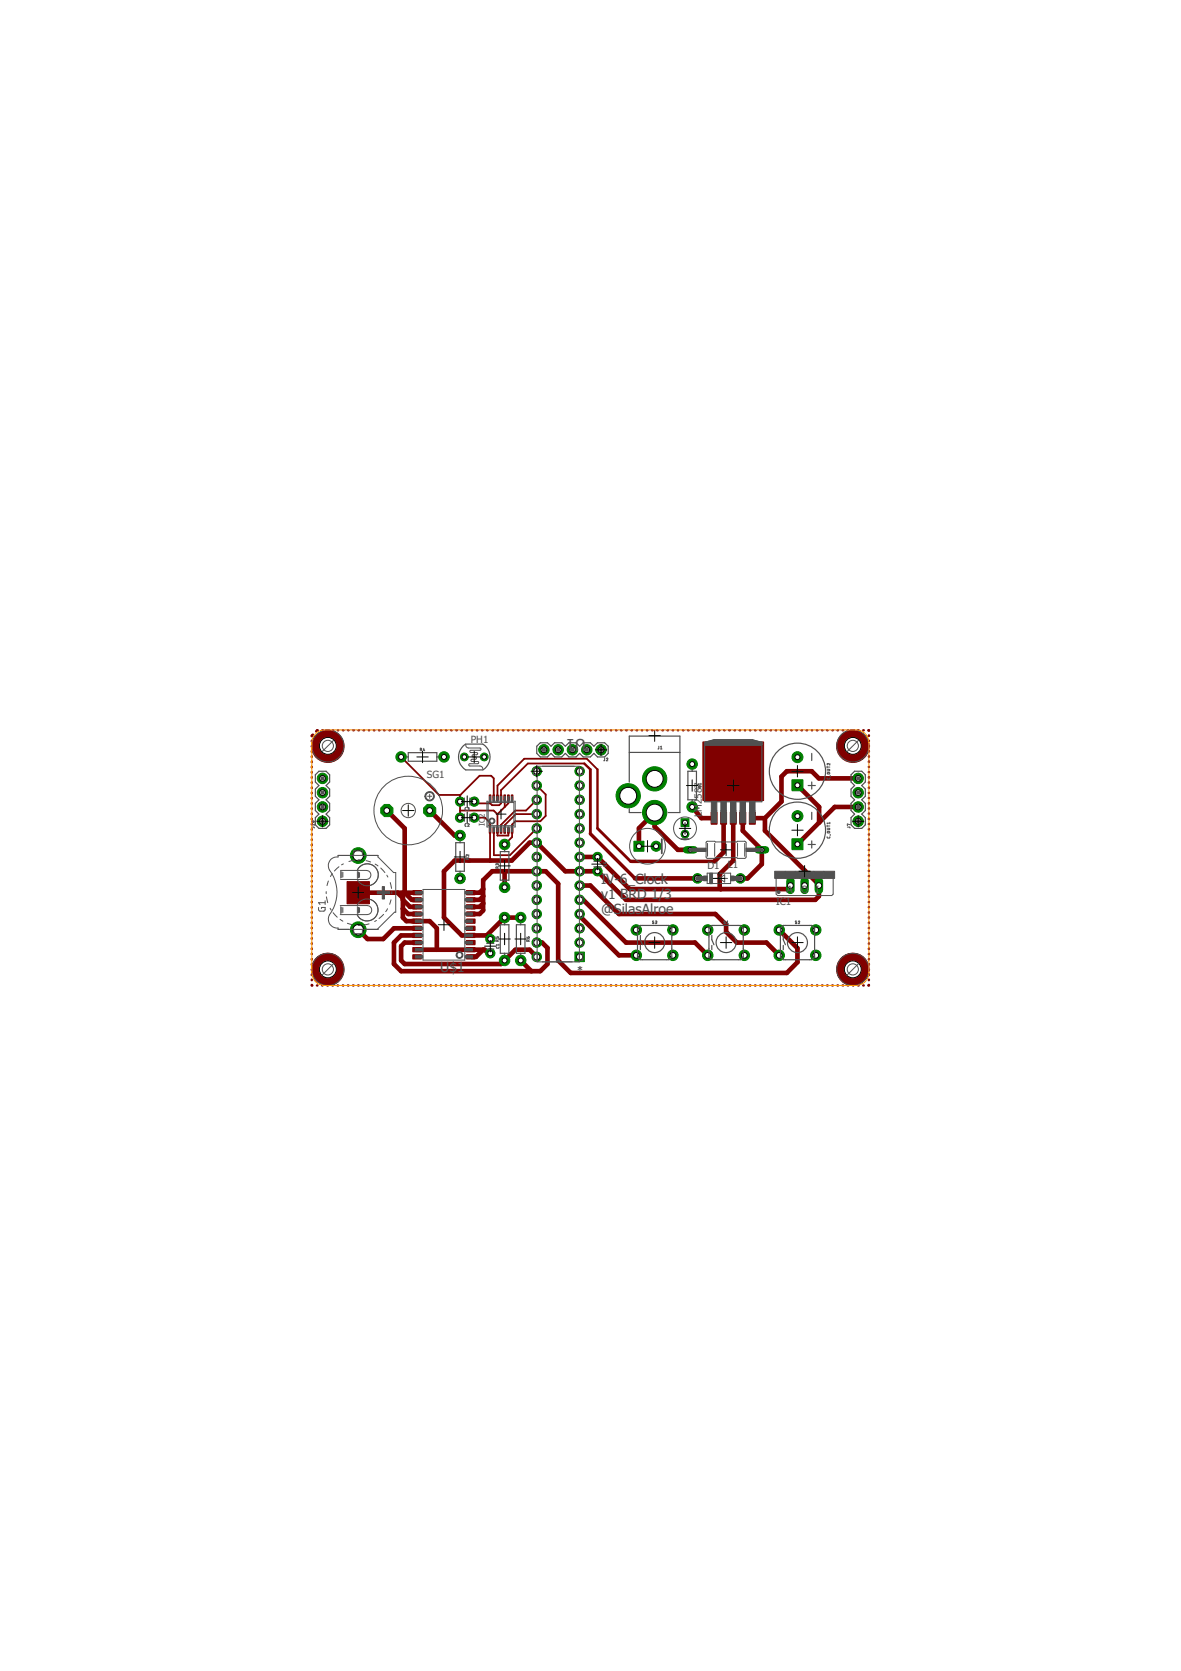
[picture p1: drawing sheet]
<svg xmlns="http://www.w3.org/2000/svg" width="210mm" height="297mm" viewBox="0 0 210 297" stroke-linecap="round" stroke-linejoin="round" font-family="sans-serif">
<defs><g id="words">
<text font-size="2.9" fill="#505050" x="104.1" y="131.3" transform="rotate(-180 104.1 131.3)">U1</text>
<g font-size="2.5" fill="#505050">
<text x="106.8" y="157.2">IV-6_Clock</text>
<text x="106.8" y="159.8">v1 BRD 1/3</text>
<text x="106.8" y="162.5">@SilasAlroe</text>
<text x="78.2" y="172.8">U$1</text>
</g>
<g font-size="1.8" fill="#505050">
<text x="83.7" y="132">PH1</text>
<text x="75.9" y="138.4">SG1</text>
<text x="124.7" y="145.2" transform="rotate(-90 124.7 145.2)">LM2587</text>
<text x="125.7" y="154.5">D1</text>
<text x="129.3" y="154.2">L1</text>
<text x="137.9" y="160.9">IC1</text>
<text x="139.8" y="158.7">A</text>
<text x="142.4" y="158.7">O</text>
<text x="144.9" y="158.7">I</text>
<text x="103.6" y="171.2" transform="rotate(-180 103.6 171.2)">*</text>
</g>
<text font-size="1.4" fill="#505050" x="86.2" y="146.8" transform="rotate(-90 86.2 146.8)">IC2</text>
</g></defs>
<g fill="#800000" stroke="#800000" stroke-width=".18">
<path d="M124.9 131.9h10.8v10.4h-10.8z"/>
<path d="M126.4 144.4h1v2.1h-1z"/>
<path d="M128.1 144.4h1v2.1h-1z"/>
<path d="M129.8 144.4h1.1v2.1h-1.1z"/>
<path d="M131.5 144.4h1v2.1h-1z"/>
<path d="M133.2 144.4h1v2.1h-1z"/>
<path d="M82.9 169.7h1.5v.8h-1.5z"/>
<path d="M82.9 168.4h1.5v.8h-1.5z"/>
<path d="M82.9 167.2h1.5v.7h-1.5z"/>
<path d="M82.9 165.9h1.5v.8h-1.5z"/>
<path d="M82.9 164.6h1.5v.8h-1.5z"/>
<path d="M82.9 163.4h1.5v.7h-1.5z"/>
<path d="M82.9 162.1h1.5v.8h-1.5z"/>
<path d="M82.9 160.8h1.5v.8h-1.5z"/>
<path d="M82.9 159.6h1.5v.7h-1.5z"/>
<path d="M82.9 158.3h1.5v.8h-1.5z"/>
<path d="M73.4 159.6h1.5v.7h-1.5z"/>
<path d="M73.4 158.3h1.5v.8h-1.5z"/>
<path d="M73.4 160.8h1.5v.8h-1.5z"/>
<path d="M73.4 162.1h1.5v.8h-1.5z"/>
<path d="M73.4 163.4h1.5v.7h-1.5z"/>
<path d="M73.4 164.6h1.5v.8h-1.5z"/>
<path d="M73.4 165.9h1.5v.8h-1.5z"/>
<path d="M73.4 167.2h1.5v.7h-1.5z"/>
<path d="M73.4 168.4h1.5v.8h-1.5z"/>
<path d="M73.4 169.7h1.5v.8h-1.5z"/>
<path d="M61.7 156.7h4v4h-4z"/>
<path d="M87 147.2h.2v.9h-.2z"/>
<path d="M87.6 147.2h.3v.9h-.3z"/>
<path d="M88.3 147.2h.3v.9h-.3z"/>
<path d="M88.9 147.2h.3v.9h-.3z"/>
<path d="M89.6 147.2h.3v.9h-.3z"/>
<path d="M90.2 147.2h.3v.9h-.3z"/>
<path d="M90.9 147.2h.3v.9h-.3z"/>
<path d="M90.9 141.3h.3v1h-.3z"/>
<path d="M90.2 141.3h.3v1h-.3z"/>
<path d="M89.6 141.3h.3v1h-.3z"/>
<path d="M88.9 141.3h.3v1h-.3z"/>
<path d="M88.3 141.3h.3v1h-.3z"/>
<path d="M87.6 141.3h.3v1h-.3z"/>
<path d="M87 141.3h.2v1h-.2z"/>
</g>
<g fill="none" stroke="#800000" stroke-width=".42">
<path d="M55.4 131.7v.1M55.4 132.6v.1M55.4 133.5v.1M55.4 134.5v.1M55.4 135.4v.1M55.4 136.3v.1M55.4 137.2v.1M55.4 138.1v.2M55.4 139.1v.1M55.4 140v.1M55.6 130.6l-.2 .3M56.5 129.8l-.3 .2"/>
<path d="M57.3 129.8h.1M58.2 129.8h.1M59.1 129.8h.1M60 129.8h.1M60.9 129.8h.1M61.9 129.8h.1M62.8 129.8h.1M63.7 129.8h.1M64.6 129.8h.1M65.5 129.8h.1M66.4 129.8h.1M67.4 129.8h.1"/>
<path d="M68.3 129.8h.1M69.2 129.8h.1M70.1 129.8h.1M71 129.8h.1M71.9 129.8h.1M72.9 129.8h.1M73.8 129.8h.1M74.7 129.8h.1M75.6 129.8h.1M76.5 129.8h.1M77.4 129.8h.1M78.3 129.8h.1"/>
<path d="M79.2 129.8h.2M80.2 129.8h.1M81.1 129.8h.1M82 129.8h.1M82.9 129.8h.1M83.8 129.8h.1M84.8 129.8h.1M85.7 129.8h.1M86.6 129.8h.1M87.5 129.8h.1M88.4 129.8h.1M89.3 129.8h.1"/>
<path d="M90.2 129.8h.1M91.2 129.8h.1M92.1 129.8h.1M93 129.8h.1M93.9 129.8h.1M94.8 129.8h.1M95.7 129.8h.1M96.6 129.8h.2M97.6 129.8h.1M98.5 129.8h.1M99.4 129.8h.1M100.3 129.8h.1"/>
<path d="M101.2 129.8h.1M102.2 129.8h.1M103.1 129.8h.1M103.8 135.7l1.1 1.1M104 129.8h.1M104.9 129.8h.1M105.8 129.8h.1M106.2 136.8v10.5M106.7 129.8h.1M107.6 129.8h.1M108.6 129.8h.1M109.5 129.8h.1"/>
<path d="M110.4 129.8h.1M111.3 129.8h.1M112.2 129.8h.1M113.1 129.8h.1M114 129.8h.2M115 129.8h.1M115.9 129.8h.1M116.8 129.8h.1M117.7 129.8h.1M118.6 129.8h.1M119.5 129.8h.2M120.5 129.8h.1"/>
<path d="M121.4 129.8h.1M122.3 129.8h.1M123.2 129.8h.1M124.1 129.8h.1M125 129.8h.1M125.9 129.8h.1M126.9 129.8h.1M127.8 129.8h.1M128.7 129.8h.1M129.6 129.8h.1M130.5 129.8h.1M131.4 129.8h.2"/>
<path d="M132.4 129.8h.1M133.3 129.8h.1M134.2 129.8h.1M135.1 129.8h.1M136 129.8h.1M136.9 129.8h.1M137.9 129.8h.1M138.8 129.8h.1M139.7 129.8h.1M140.6 129.8h.1M141.5 129.8h.1M142.4 129.8h.1"/>
<path d="M143.3 129.8h.1M144.3 129.8h.1M145.2 129.8h.1M146.1 129.8h.1M147 129.8h.1M147.9 129.8h.1M148.8 129.8h.1M149.8 129.8h.1M150.7 129.8h.1M151.6 129.8h.1M152.5 129.8h.1M153.4 129.8h.1"/>
<path d="M154.3 129.8l.1 .1M154.4 130.7v.1M154.4 131.7v.1M154.4 132.6v.1M154.4 133.5v.1M154.4 134.4v.1M154.4 135.3v.2M154.4 136.3v.1M154.4 137.2v.1M154.4 138.1v.1M154.4 139v.1M154.4 140v.1"/>
<path d="M55.4 140.9v.1M55.4 141.8v.1M55.4 142.7v.2M55.4 143.7v.1M55.4 144.6v.1M55.4 145.5v.1M55.4 146.5v.1M55.4 147.4v.1M55.4 148.3v.1M55.4 149.2v.1M55.4 150.1v.2M55.4 151.1v.1"/>
<path d="M55.4 152v.1M55.4 152.9v.1M55.4 153.8v.1M55.4 154.7v.2M55.4 155.7v.1M55.4 156.6v.1M55.4 157.5v.1M55.4 158.5v.1M55.4 159.4v.1M154.4 140.9v.1M154.4 141.8v.1M154.4 142.7v.2"/>
<path d="M154.4 143.7v.1M154.4 144.6v.1M154.4 145.5v.1M154.4 146.4v.1M154.4 147.4v.1M154.4 148.3v.1M154.4 149.2v.1M154.4 150.1v.1M154.4 151v.2M154.4 152v.1M154.4 152.9v.1M154.4 153.8v.1"/>
<path d="M154.4 154.7v.2M154.4 155.7v.1M154.4 156.6v.1M154.4 157.5v.1M154.4 158.4v.2M154.4 159.4v.1M55.4 160.3v.1M55.4 161.2v.1M55.4 162.1v.1M55.4 163.1v.1M55.4 164v.1M55.4 164.9v.1"/>
<path d="M55.4 165.8v.1M55.4 166.8v.1M55.4 167.7v.1M55.4 168.6v.1M55.4 169.5v.1M55.4 170.5v.1M55.4 171.4v.1M55.4 172.3v.1M55.4 173.2v.1M55.4 174.1v.1M55.4 175.1l.1 .1M56.3 175.2h.1"/>
<path d="M57.3 175.2h.1M58.2 175.2h.1M59.1 175.2h.1M60 175.2h.1M60.9 175.2h.1M61.8 175.2h.1M62.7 175.2h.1M63.6 175.2h.2M64.6 175.2h.1M65.5 175.2h.1M66.4 175.2h.1M67.3 175.2h.1"/>
<path d="M68.2 175.2h.1M69.2 175.2h.1M70.1 175.2h.1M71 175.2h.1M71.9 175.2h.1M72.8 175.2h.1M73.7 175.2h.1M74.7 175.2h.1M75.6 175.2h.1M76.5 175.2h.1M77.4 175.2h.1M78.3 175.2h.1"/>
<path d="M79.2 175.2h.1M80.1 175.2h.1M81.1 175.2h.1M82 175.2h.1M82.9 175.2h.1M83.8 175.2h.1M84.7 175.2h.1M85.6 175.2h.1M86.6 175.2h.1M87.5 175.2h.1M88.4 175.2h.1M89.3 175.2h.1"/>
<path d="M90.2 175.2h.1M91.1 175.2h.1M92.1 175.2h.1M93 175.2h.1M93.9 175.2h.1M94.8 175.2h.1M95.7 175.2h.1M96.6 175.2h.1M97.6 175.2h.1M98.5 175.2h.1M99.4 175.2h.1M100.3 175.2h.1"/>
<path d="M101.2 175.2h.1M102.1 175.2h.1M103 175.2h.1M103.9 175.2h.2M104.9 175.2h.1M105.8 175.2h.1M106.7 175.2h.1M107.6 175.2h.1M108.5 175.2h.1M109.5 175.2h.1M110.4 175.2h.1M111.3 175.2h.1"/>
<path d="M112.2 175.2h.1M113.1 175.2h.1M114 175.2h.1M115 175.2h.1M115.9 175.2h.1M116.8 175.2h.1M117.7 175.2h.1M118.6 175.2h.1M119.5 175.2h.1M120.4 175.2h.1M121.4 175.2h.1M122.3 175.2h.1"/>
<path d="M123.2 175.2h.1M124.1 175.2h.1M125 175.2h.1M125.9 175.2h.1M126.9 175.2h.1M127.8 175.2h.1M128.7 175.2h.1M129.6 175.2h.1M130.5 175.2h.1M131.4 175.2h.1M132.4 175.2h.1M133.3 175.2h.1"/>
<path d="M134.2 175.2h.1M135.1 175.2h.1M136 175.2h.1M136.9 175.2h.1M137.8 175.2h.1M138.8 175.2h.1M139.7 175.2h.1M140.6 175.2h.1M141.5 175.2h.1M142.4 175.2h.1M143.3 175.2h.1M144.3 175.2h.1"/>
<path d="M145.2 175.2h.1M146.1 175.2h.1M147 175.2h.1M147.9 175.2h.1M148.8 175.2h.1M149.8 175.2h.1M150.7 175.2h.1M151.6 175.2h.1M152.5 175.2h.1M153.4 175.2h.1M154.4 160.3v.1M154.4 161.2v.1"/>
<path d="M154.4 162.1v.1M154.4 163v.2M154.4 164v.1M154.4 164.9v.1M154.4 165.8v.1M154.4 166.8v.1M154.4 167.7v.1M154.4 168.6v.1M154.4 169.5v.1M154.4 170.5v.1M154.4 171.4v.1M154.4 172.3v.1"/>
<path d="M154.4 173.2v.1M154.4 174.1v.1M154.4 175.1l-.1 .1"/>
</g>
<g fill="none" stroke="#800000" stroke-width=".83">
<path d="M141.7 139.6l3.9 3.8v2.8M152.5 138.4h-7l-1.2-1.3h-4.5l-.9 .9v4.5l-2.9 2.9M63.7 158.7h10.4M68.7 144.1l3.2 3.2v11.4l1.3 1.3h.9M70.7 158.7l.9 .9M71.6 158.7v4.4l.6 .6h4.2l1.2 1.3v3.8M71.6 160l1.3 1.2h1.2M76.4 144.1l4.4 4.4h1M85.9 158.1l-.7 .6h-1.5M85.9 159.3l-.7 .7h-1.5M89.7 154.9v2.8M103 157.4h1.9l5.1 5.1h17.1l2 1.9v1.3l1.9 1.9h5.2l2.3 2.2"/>
<path d="M103 160h.7l7.6 7.6h12.2l2.3 2.2M103 152.3h3.2l5.7 5.8h27.9l.7-.7M112.9 156.1h11.1M116.4 144.4h.5M116.4 144.4l-2.8 2.8v3.2M116.4 144.4v2.5l4.1 4.2h2.2M123 143.4l1.7 2h2.2M128.6 145.4v6.1l-1.6 1.6M130.3 145.4v7.6l-2.4 2.4v2.5l.2 .2M132 145.4v2.3l3.4 3.4v2.5l-2.5 2.5h-1.3M133.7 145.4h2.3M136 145.4v2.3l9.5 9.5v2.1l-.6 .7h-33.6l-5.1-5.1h-5.7l-5.1-5.1h-1.3l-3.1 3.2h-10.2l-1.9 1.9v8.2l3.2 3.2h4.4"/>
<path d="M152.5 143.4h-4.1l-6.7 6.7v-.6M71.6 161.5l1 1h1.5M74.1 168.8h12l.7 .7h.3M74.1 167.6h-2.2l-.6 .6v2.5l.6 .7h17.1l2.6-2.6h2.5l1.3 1.3M74.1 166.3h-2.8l-1.3 1.3v3.8l1.3 1.2h24.7l1.3-1.2v-2.9l-.9-.9h-1M74.1 165h-4.1l-1.9 1.9h-2.8l-1.6-1.6M83.7 162.5h1.5l.7-.7v-5.3l1.6-1.6h9.5l2.2 2.2v13.6l2.2 2.3h38.4l1.9-2v-2.4l-3.2-3.3M85.9 160.6l-.7 .6h-1.5M85.9 168.8l-1.3 1.3h-.9M86.5 166.3l.6 .6M92.5 163.1h-2.8l-3.2 3.2M92.5 170.7l1.9 1.9"/>
<path d="M103 162.5h-.3l7.3 7.3h3.1"/>
</g>
<g fill="none" stroke="#800000" stroke-width=".32">
<path d="M71.3 134.6l6.7 6.7h3.8M95.4 139.6l1.6 1.6v3.8l-1 1h-4.4l-.6 .6v2.2l-1.3 1.3M103.8 135.7h-10l-4.8 4.8v2.3l-.3 .3h-1.2l-.4-.3v-1M106.2 136.8l-1.9-1.9h-11.1l-4.8 4.8v2.1M81.8 144.1h5.9l.7 .6M81.8 141.3l3.4-3.4h2.1l.5 .5v3.4M81.8 141.3v4.1M83.3 152.9l.1 .1M84.3 145.4h1.9l.9 .9v6.7M84.3 142.5l.3 .3h2.5M88.4 144.7v3.8h1.9l.1-.9M89.7 141.8v1.6"/>
<path d="M90.4 141.8v1l-2 1.9M95.4 144.7h-3.7l-2 2v.9M95.4 142.2l-1.9 1.9h-1.9l-2.6 2.5v1M95.4 147.3l-4.8 4.7h-2.8v-4.4"/>
</g>
<path d="M104.9 136.8v11.4M106.2 147.3l5.9 5.8h.1" fill="none" stroke="#800000" stroke-width=".51"/>
<path d="M104.9 148.2l8 7.9M112.2 153.1h14.8" fill="none" stroke="#800000" stroke-width=".61"/>
<circle cx="121.8" cy="148.3" r=".7" fill="#008000" stroke="#008000" stroke-width=".18"/>
<circle cx="121.8" cy="148.3" r=".44" fill="#fff" stroke="#000" stroke-width=".18"/>
<path d="M121.1 145.5h1.3v1.4h-1.3z" fill="#008000" stroke="#008000" stroke-width=".18"/>
<circle cx="121.8" cy="146.2" r=".44" fill="#fff" stroke="#000" stroke-width=".18"/>
<path d="M112.7 149.5h1.7v1.8h-1.7z" fill="#008000" stroke="#008000" stroke-width=".18"/>
<circle cx="113.6" cy="150.4" r=".44" fill="#fff" stroke="#000" stroke-width=".18"/>
<circle cx="116.6" cy="150.4" r=".89" fill="#008000" stroke="#008000" stroke-width=".18"/>
<circle cx="116.6" cy="150.4" r=".44" fill="#fff" stroke="#000" stroke-width=".18"/>
<circle cx="141.7" cy="145.1" r=".97" fill="#008000" stroke="#008000" stroke-width=".18"/>
<circle cx="141.7" cy="145.1" r=".44" fill="#fff" stroke="#000" stroke-width=".18"/>
<path d="M140.8 149.1h1.9v1.9h-1.9z" fill="#008000" stroke="#008000" stroke-width=".18"/>
<circle cx="141.7" cy="150.1" r=".44" fill="#fff" stroke="#000" stroke-width=".18"/>
<circle cx="141.7" cy="134.6" r=".97" fill="#008000" stroke="#008000" stroke-width=".18"/>
<circle cx="141.7" cy="134.6" r=".44" fill="#fff" stroke="#000" stroke-width=".18"/>
<path d="M140.8 138.6h1.9v2h-1.9z" fill="#008000" stroke="#008000" stroke-width=".18"/>
<circle cx="141.7" cy="139.6" r=".44" fill="#fff" stroke="#000" stroke-width=".18"/>
<circle cx="124" cy="156.1" r=".85" fill="#008000" stroke="#008000" stroke-width=".18"/>
<circle cx="124" cy="156.1" r=".55" fill="#fff" stroke="#000" stroke-width=".18"/>
<circle cx="131.6" cy="156.1" r=".85" fill="#008000" stroke="#008000" stroke-width=".18"/>
<circle cx="131.6" cy="156.1" r=".55" fill="#fff" stroke="#000" stroke-width=".18"/>
<path d="M134.7 151.1h1.4" fill="none" stroke="#008000" stroke-width="1.3"/>
<circle cx="135.4" cy="151.1" r=".4" fill="#fff" stroke="#000" stroke-width=".18"/>
<path d="M122 151.1h1.4" fill="none" stroke="#008000" stroke-width="1.3"/>
<circle cx="122.7" cy="151.1" r=".4" fill="#fff" stroke="#000" stroke-width=".18"/>
<circle cx="123" cy="135.8" r=".93" fill="#008000" stroke="#008000" stroke-width=".18"/>
<circle cx="123" cy="135.8" r=".44" fill="#fff" stroke="#000" stroke-width=".18"/>
<circle cx="123" cy="143.4" r=".93" fill="#008000" stroke="#008000" stroke-width=".18"/>
<circle cx="123" cy="143.4" r=".44" fill="#fff" stroke="#000" stroke-width=".18"/>
<circle cx="116.4" cy="144.4" r="2.16" fill="#008000" stroke="#008000" stroke-width=".18"/>
<circle cx="116.4" cy="144.4" r="1.5" fill="#fff" stroke="#000" stroke-width=".18"/>
<circle cx="116.4" cy="138.5" r="2.16" fill="#008000" stroke="#008000" stroke-width=".18"/>
<circle cx="116.4" cy="138.5" r="1.5" fill="#fff" stroke="#000" stroke-width=".18"/>
<circle cx="111.7" cy="141.5" r="2.16" fill="#008000" stroke="#008000" stroke-width=".18"/>
<circle cx="111.7" cy="141.5" r="1.5" fill="#fff" stroke="#000" stroke-width=".18"/>
<circle cx="152.5" cy="146" r=".93" fill="#008000" stroke="#008000" stroke-width=".18"/>
<circle cx="152.5" cy="146" r=".51" fill="#fff" stroke="#000" stroke-width=".18"/>
<circle cx="152.5" cy="143.4" r=".93" fill="#008000" stroke="#008000" stroke-width=".18"/>
<circle cx="152.5" cy="143.4" r=".51" fill="#fff" stroke="#000" stroke-width=".18"/>
<circle cx="152.5" cy="140.9" r=".93" fill="#008000" stroke="#008000" stroke-width=".18"/>
<circle cx="152.5" cy="140.9" r=".51" fill="#fff" stroke="#000" stroke-width=".18"/>
<circle cx="152.5" cy="138.4" r=".93" fill="#008000" stroke="#008000" stroke-width=".18"/>
<circle cx="152.5" cy="138.4" r=".51" fill="#fff" stroke="#000" stroke-width=".18"/>
<circle cx="57.3" cy="146" r=".93" fill="#008000" stroke="#008000" stroke-width=".18"/>
<circle cx="57.3" cy="146" r=".51" fill="#fff" stroke="#000" stroke-width=".18"/>
<circle cx="57.3" cy="143.4" r=".93" fill="#008000" stroke="#008000" stroke-width=".18"/>
<circle cx="57.3" cy="143.4" r=".51" fill="#fff" stroke="#000" stroke-width=".18"/>
<circle cx="57.3" cy="140.9" r=".93" fill="#008000" stroke="#008000" stroke-width=".18"/>
<circle cx="57.3" cy="140.9" r=".51" fill="#fff" stroke="#000" stroke-width=".18"/>
<circle cx="57.3" cy="138.4" r=".93" fill="#008000" stroke="#008000" stroke-width=".18"/>
<circle cx="57.3" cy="138.4" r=".51" fill="#fff" stroke="#000" stroke-width=".18"/>
<circle cx="86.1" cy="134.6" r=".7" fill="#008000" stroke="#008000" stroke-width=".18"/>
<circle cx="86.1" cy="134.6" r=".4" fill="#fff" stroke="#000" stroke-width=".18"/>
<circle cx="82.5" cy="134.6" r=".7" fill="#008000" stroke="#008000" stroke-width=".18"/>
<circle cx="82.5" cy="134.6" r=".4" fill="#fff" stroke="#000" stroke-width=".18"/>
<circle cx="71.3" cy="134.6" r=".93" fill="#008000" stroke="#008000" stroke-width=".18"/>
<circle cx="71.3" cy="134.6" r=".44" fill="#fff" stroke="#000" stroke-width=".18"/>
<circle cx="78.9" cy="134.6" r=".93" fill="#008000" stroke="#008000" stroke-width=".18"/>
<circle cx="78.9" cy="134.6" r=".44" fill="#fff" stroke="#000" stroke-width=".18"/>
<circle cx="125.8" cy="165.3" r=".93" fill="#008000" stroke="#008000" stroke-width=".18"/>
<circle cx="125.8" cy="165.3" r=".51" fill="#fff" stroke="#000" stroke-width=".18"/>
<circle cx="132.3" cy="165.3" r=".93" fill="#008000" stroke="#008000" stroke-width=".18"/>
<circle cx="132.3" cy="165.3" r=".51" fill="#fff" stroke="#000" stroke-width=".18"/>
<circle cx="125.8" cy="169.8" r=".93" fill="#008000" stroke="#008000" stroke-width=".18"/>
<circle cx="125.8" cy="169.8" r=".51" fill="#fff" stroke="#000" stroke-width=".18"/>
<circle cx="132.3" cy="169.8" r=".93" fill="#008000" stroke="#008000" stroke-width=".18"/>
<circle cx="132.3" cy="169.8" r=".51" fill="#fff" stroke="#000" stroke-width=".18"/>
<path d="M140.5 156.7v1.5" fill="none" stroke="#008000" stroke-width="1.5"/>
<circle cx="140.5" cy="157.4" r=".51" fill="#fff" stroke="#000" stroke-width=".18"/>
<path d="M143 156.7v1.5" fill="none" stroke="#008000" stroke-width="1.5"/>
<circle cx="143" cy="157.4" r=".51" fill="#fff" stroke="#000" stroke-width=".18"/>
<path d="M145.5 156.7v1.5" fill="none" stroke="#008000" stroke-width="1.5"/>
<circle cx="145.5" cy="157.4" r=".51" fill="#fff" stroke="#000" stroke-width=".18"/>
<circle cx="138.5" cy="165.3" r=".93" fill="#008000" stroke="#008000" stroke-width=".18"/>
<circle cx="138.5" cy="165.3" r=".51" fill="#fff" stroke="#000" stroke-width=".18"/>
<circle cx="145" cy="165.3" r=".93" fill="#008000" stroke="#008000" stroke-width=".18"/>
<circle cx="145" cy="165.3" r=".51" fill="#fff" stroke="#000" stroke-width=".18"/>
<circle cx="138.5" cy="169.8" r=".93" fill="#008000" stroke="#008000" stroke-width=".18"/>
<circle cx="138.5" cy="169.8" r=".51" fill="#fff" stroke="#000" stroke-width=".18"/>
<circle cx="145" cy="169.8" r=".93" fill="#008000" stroke="#008000" stroke-width=".18"/>
<circle cx="145" cy="169.8" r=".51" fill="#fff" stroke="#000" stroke-width=".18"/>
<circle cx="113.1" cy="165.3" r=".93" fill="#008000" stroke="#008000" stroke-width=".18"/>
<circle cx="113.1" cy="165.3" r=".51" fill="#fff" stroke="#000" stroke-width=".18"/>
<circle cx="119.6" cy="165.3" r=".93" fill="#008000" stroke="#008000" stroke-width=".18"/>
<circle cx="119.6" cy="165.3" r=".51" fill="#fff" stroke="#000" stroke-width=".18"/>
<circle cx="113.1" cy="169.8" r=".93" fill="#008000" stroke="#008000" stroke-width=".18"/>
<circle cx="113.1" cy="169.8" r=".51" fill="#fff" stroke="#000" stroke-width=".18"/>
<circle cx="119.6" cy="169.8" r=".93" fill="#008000" stroke="#008000" stroke-width=".18"/>
<circle cx="119.6" cy="169.8" r=".51" fill="#fff" stroke="#000" stroke-width=".18"/>
<circle cx="68.7" cy="144.1" r="1.17" fill="#008000" stroke="#008000" stroke-width=".18"/>
<circle cx="68.7" cy="144.1" r=".51" fill="#fff" stroke="#000" stroke-width=".18"/>
<circle cx="76.4" cy="144.1" r="1.17" fill="#008000" stroke="#008000" stroke-width=".18"/>
<circle cx="76.4" cy="144.1" r=".51" fill="#fff" stroke="#000" stroke-width=".18"/>
<circle cx="81.8" cy="148.5" r=".93" fill="#008000" stroke="#008000" stroke-width=".18"/>
<circle cx="81.8" cy="148.5" r=".44" fill="#fff" stroke="#000" stroke-width=".18"/>
<circle cx="81.8" cy="156.1" r=".93" fill="#008000" stroke="#008000" stroke-width=".18"/>
<circle cx="81.8" cy="156.1" r=".44" fill="#fff" stroke="#000" stroke-width=".18"/>
<path d="M102.2 169.2h1.7v1.7h-1.7z" fill="#008000" stroke="#008000" stroke-width=".18"/>
<circle cx="103" cy="170.1" r=".55" fill="#fff" stroke="#000" stroke-width=".18"/>
<circle cx="103" cy="167.6" r=".85" fill="#008000" stroke="#008000" stroke-width=".18"/>
<circle cx="103" cy="167.6" r=".55" fill="#fff" stroke="#000" stroke-width=".18"/>
<circle cx="103" cy="165" r=".85" fill="#008000" stroke="#008000" stroke-width=".18"/>
<circle cx="103" cy="165" r=".55" fill="#fff" stroke="#000" stroke-width=".18"/>
<circle cx="103" cy="162.5" r=".85" fill="#008000" stroke="#008000" stroke-width=".18"/>
<circle cx="103" cy="162.5" r=".55" fill="#fff" stroke="#000" stroke-width=".18"/>
<circle cx="103" cy="160" r=".85" fill="#008000" stroke="#008000" stroke-width=".18"/>
<circle cx="103" cy="160" r=".55" fill="#fff" stroke="#000" stroke-width=".18"/>
<circle cx="103" cy="157.4" r=".85" fill="#008000" stroke="#008000" stroke-width=".18"/>
<circle cx="103" cy="157.4" r=".55" fill="#fff" stroke="#000" stroke-width=".18"/>
<circle cx="103" cy="154.9" r=".85" fill="#008000" stroke="#008000" stroke-width=".18"/>
<circle cx="103" cy="154.9" r=".55" fill="#fff" stroke="#000" stroke-width=".18"/>
<circle cx="103" cy="152.3" r=".85" fill="#008000" stroke="#008000" stroke-width=".18"/>
<circle cx="103" cy="152.3" r=".55" fill="#fff" stroke="#000" stroke-width=".18"/>
<circle cx="103" cy="149.8" r=".85" fill="#008000" stroke="#008000" stroke-width=".18"/>
<circle cx="103" cy="149.8" r=".55" fill="#fff" stroke="#000" stroke-width=".18"/>
<circle cx="103" cy="147.3" r=".85" fill="#008000" stroke="#008000" stroke-width=".18"/>
<circle cx="103" cy="147.3" r=".55" fill="#fff" stroke="#000" stroke-width=".18"/>
<circle cx="103" cy="144.7" r=".85" fill="#008000" stroke="#008000" stroke-width=".18"/>
<circle cx="103" cy="144.7" r=".55" fill="#fff" stroke="#000" stroke-width=".18"/>
<circle cx="103" cy="142.2" r=".85" fill="#008000" stroke="#008000" stroke-width=".18"/>
<circle cx="103" cy="142.2" r=".55" fill="#fff" stroke="#000" stroke-width=".18"/>
<circle cx="103" cy="139.6" r=".85" fill="#008000" stroke="#008000" stroke-width=".18"/>
<circle cx="103" cy="139.6" r=".55" fill="#fff" stroke="#000" stroke-width=".18"/>
<circle cx="103" cy="137.1" r=".85" fill="#008000" stroke="#008000" stroke-width=".18"/>
<circle cx="103" cy="137.1" r=".55" fill="#fff" stroke="#000" stroke-width=".18"/>
<circle cx="95.4" cy="137.1" r=".85" fill="#008000" stroke="#008000" stroke-width=".18"/>
<circle cx="95.4" cy="137.1" r=".55" fill="#fff" stroke="#000" stroke-width=".18"/>
<circle cx="95.4" cy="139.6" r=".85" fill="#008000" stroke="#008000" stroke-width=".18"/>
<circle cx="95.4" cy="139.6" r=".55" fill="#fff" stroke="#000" stroke-width=".18"/>
<circle cx="95.4" cy="142.2" r=".85" fill="#008000" stroke="#008000" stroke-width=".18"/>
<circle cx="95.4" cy="142.2" r=".55" fill="#fff" stroke="#000" stroke-width=".18"/>
<circle cx="95.4" cy="144.7" r=".85" fill="#008000" stroke="#008000" stroke-width=".18"/>
<circle cx="95.4" cy="144.7" r=".55" fill="#fff" stroke="#000" stroke-width=".18"/>
<circle cx="95.4" cy="147.3" r=".85" fill="#008000" stroke="#008000" stroke-width=".18"/>
<circle cx="95.4" cy="147.3" r=".55" fill="#fff" stroke="#000" stroke-width=".18"/>
<circle cx="95.4" cy="149.8" r=".85" fill="#008000" stroke="#008000" stroke-width=".18"/>
<circle cx="95.4" cy="149.8" r=".55" fill="#fff" stroke="#000" stroke-width=".18"/>
<circle cx="95.4" cy="152.3" r=".85" fill="#008000" stroke="#008000" stroke-width=".18"/>
<circle cx="95.4" cy="152.3" r=".55" fill="#fff" stroke="#000" stroke-width=".18"/>
<circle cx="95.4" cy="154.9" r=".85" fill="#008000" stroke="#008000" stroke-width=".18"/>
<circle cx="95.4" cy="154.9" r=".55" fill="#fff" stroke="#000" stroke-width=".18"/>
<circle cx="95.4" cy="157.4" r=".85" fill="#008000" stroke="#008000" stroke-width=".18"/>
<circle cx="95.4" cy="157.4" r=".55" fill="#fff" stroke="#000" stroke-width=".18"/>
<circle cx="95.4" cy="160" r=".85" fill="#008000" stroke="#008000" stroke-width=".18"/>
<circle cx="95.4" cy="160" r=".55" fill="#fff" stroke="#000" stroke-width=".18"/>
<circle cx="95.4" cy="162.5" r=".85" fill="#008000" stroke="#008000" stroke-width=".18"/>
<circle cx="95.4" cy="162.5" r=".55" fill="#fff" stroke="#000" stroke-width=".18"/>
<circle cx="95.4" cy="165" r=".85" fill="#008000" stroke="#008000" stroke-width=".18"/>
<circle cx="95.4" cy="165" r=".55" fill="#fff" stroke="#000" stroke-width=".18"/>
<circle cx="95.4" cy="167.6" r=".85" fill="#008000" stroke="#008000" stroke-width=".18"/>
<circle cx="95.4" cy="167.6" r=".55" fill="#fff" stroke="#000" stroke-width=".18"/>
<circle cx="95.4" cy="170.1" r=".85" fill="#008000" stroke="#008000" stroke-width=".18"/>
<circle cx="95.4" cy="170.1" r=".55" fill="#fff" stroke="#000" stroke-width=".18"/>
<circle cx="63.7" cy="165.3" r="1.4" fill="#008000" stroke="#008000" stroke-width=".18"/>
<circle cx="63.7" cy="165.3" r=".93" fill="#fff" stroke="#000" stroke-width=".18"/>
<circle cx="63.7" cy="152.1" r="1.4" fill="#008000" stroke="#008000" stroke-width=".18"/>
<circle cx="63.7" cy="152.1" r=".93" fill="#fff" stroke="#000" stroke-width=".18"/>
<circle cx="106.8" cy="133.3" r=".93" fill="#008000" stroke="#008000" stroke-width=".18"/>
<circle cx="106.8" cy="133.3" r=".51" fill="#fff" stroke="#000" stroke-width=".18"/>
<circle cx="104.3" cy="133.3" r=".93" fill="#008000" stroke="#008000" stroke-width=".18"/>
<circle cx="104.3" cy="133.3" r=".51" fill="#fff" stroke="#000" stroke-width=".18"/>
<circle cx="101.7" cy="133.3" r=".93" fill="#008000" stroke="#008000" stroke-width=".18"/>
<circle cx="101.7" cy="133.3" r=".51" fill="#fff" stroke="#000" stroke-width=".18"/>
<circle cx="99.2" cy="133.3" r=".93" fill="#008000" stroke="#008000" stroke-width=".18"/>
<circle cx="99.2" cy="133.3" r=".51" fill="#fff" stroke="#000" stroke-width=".18"/>
<circle cx="96.7" cy="133.3" r=".93" fill="#008000" stroke="#008000" stroke-width=".18"/>
<circle cx="96.7" cy="133.3" r=".51" fill="#fff" stroke="#000" stroke-width=".18"/>
<circle cx="89.7" cy="157.7" r=".93" fill="#008000" stroke="#008000" stroke-width=".18"/>
<circle cx="89.7" cy="157.7" r=".44" fill="#fff" stroke="#000" stroke-width=".18"/>
<circle cx="89.7" cy="150.1" r=".93" fill="#008000" stroke="#008000" stroke-width=".18"/>
<circle cx="89.7" cy="150.1" r=".44" fill="#fff" stroke="#000" stroke-width=".18"/>
<circle cx="89.7" cy="170.7" r=".93" fill="#008000" stroke="#008000" stroke-width=".18"/>
<circle cx="89.7" cy="170.7" r=".44" fill="#fff" stroke="#000" stroke-width=".18"/>
<circle cx="89.7" cy="163.1" r=".93" fill="#008000" stroke="#008000" stroke-width=".18"/>
<circle cx="89.7" cy="163.1" r=".44" fill="#fff" stroke="#000" stroke-width=".18"/>
<circle cx="92.5" cy="163.1" r=".93" fill="#008000" stroke="#008000" stroke-width=".18"/>
<circle cx="92.5" cy="163.1" r=".44" fill="#fff" stroke="#000" stroke-width=".18"/>
<circle cx="92.5" cy="170.7" r=".93" fill="#008000" stroke="#008000" stroke-width=".18"/>
<circle cx="92.5" cy="170.7" r=".44" fill="#fff" stroke="#000" stroke-width=".18"/>
<circle cx="87.1" cy="166.9" r=".83" fill="#008000" stroke="#008000" stroke-width=".18"/>
<circle cx="87.1" cy="166.9" r=".44" fill="#fff" stroke="#000" stroke-width=".18"/>
<circle cx="87.1" cy="169.5" r=".83" fill="#008000" stroke="#008000" stroke-width=".18"/>
<circle cx="87.1" cy="169.5" r=".44" fill="#fff" stroke="#000" stroke-width=".18"/>
<circle cx="84.3" cy="145.4" r=".83" fill="#008000" stroke="#008000" stroke-width=".18"/>
<circle cx="84.3" cy="145.4" r=".44" fill="#fff" stroke="#000" stroke-width=".18"/>
<circle cx="81.8" cy="145.4" r=".83" fill="#008000" stroke="#008000" stroke-width=".18"/>
<circle cx="81.8" cy="145.4" r=".44" fill="#fff" stroke="#000" stroke-width=".18"/>
<circle cx="84.3" cy="142.5" r=".83" fill="#008000" stroke="#008000" stroke-width=".18"/>
<circle cx="84.3" cy="142.5" r=".44" fill="#fff" stroke="#000" stroke-width=".18"/>
<circle cx="81.8" cy="142.5" r=".83" fill="#008000" stroke="#008000" stroke-width=".18"/>
<circle cx="81.8" cy="142.5" r=".44" fill="#fff" stroke="#000" stroke-width=".18"/>
<circle cx="106.2" cy="152.3" r=".83" fill="#008000" stroke="#008000" stroke-width=".18"/>
<circle cx="106.2" cy="152.3" r=".44" fill="#fff" stroke="#000" stroke-width=".18"/>
<circle cx="106.2" cy="154.9" r=".83" fill="#008000" stroke="#008000" stroke-width=".18"/>
<circle cx="106.2" cy="154.9" r=".44" fill="#fff" stroke="#000" stroke-width=".18"/>
<g fill="#800000" stroke="#800000" stroke-width=".18">
<path d="M56 170.5a2.88 2.88 0 0 1 4.6 .2 2.88 2.88 0 0 1-1.5 4.3 2.88 2.88 0 0 1-3.7-2.7h2.5a.35 .35 0 0 1 .5-.4 .35 .35 0 0 1 .1 .6 .35 .35 0 0 1-.6-.1l-2.5-.1 .1-.6z" fill-rule="evenodd"/>
<path d="M56 130.9a2.89 2.89 0 0 1 4.7 .1 2.89 2.89 0 0 1-1.5 4.4 2.89 2.89 0 0 1-3.8-2.7h2.5a.35 .35 0 0 1 .5-.4 .35 .35 0 0 1 .1 .6 .35 .35 0 0 1-.6-.2h-2.5l.1-.7z" fill-rule="evenodd"/>
<path d="M149.3 130.9a2.88 2.88 0 0 1 4.7 .1 2.88 2.88 0 0 1-1.6 4.4 2.88 2.88 0 0 1-3.7-2.7h2.5a.35 .35 0 0 1 .6-.3 .35 .35 0 0 1 0 .6 .35 .35 0 0 1-.6-.3h-2.5l.3-1.3z" fill-rule="evenodd"/>
<path d="M149.8 170.1a2.89 2.89 0 0 1 4.4 .9 2.89 2.89 0 0 1-2 4.1 2.89 2.89 0 0 1-3.5-2.8h2.5a.35 .35 0 0 1 .6-.2 .35 .35 0 0 1 0 .6 .35 .35 0 0 1-.6-.3l-2.5-.1a2.87 2.87 0 0 1 1.1-2.2z" fill-rule="evenodd"/>
</g>
<g fill="none" stroke="#505050" stroke-width=".18">
<path d="M74.7 133.3h.1M74.8 133.3l.2-.2-.3-.1v.5M74.8 133.3l.2 .2M75.3 133l-.1 .4h.3M75.4 133.3v.2M82.8 132.4l.1 .4 .2 .1 2.2 .1 .2 .1v.2l-.2 .1-1.8 .1v.2l.2 .1h1l.2 .2-.2 .2-.8 .1 .1 .2 .6 .1 .1 .3-.9 .1-.1 .3 1.3 .1 .1 .2-.2 .2h-1.5l-.1 .2 .2 .2h1.9l.3 .2 .1 .3M94.8 139.1h.7v1.1h-.7zM94.8 136.5h.7v1.2h-.7zM95.5 136.2h7.5v34.8h-7.5zM103 136.5h.6v1.2h-.6zM103 139.1h.6v1.1h-.6zM107.5 134.7v.5h-.2"/>
<path d="M107.8 134.9l.2-.1-.2 .4h.2M117.1 132.7v.3l-.2 .1M117.4 133.1h.3M117.4 132.8l.1-.1v.4M124.6 139.8l-.2 .1M124.6 139.4h-.5l.1 .1M124.6 139.2v.3M147 138.3l.1 .2h.3l.1-.2M147 136.8h.5l-.1 .2h-.4M147 136.2v.3M147 136.4h.5M147.1 137.4h.3l.1 .1-.4 .1z"/>
<path d="M147.5 135.7v.3l-.5-.3 .1 .3M147.6 137.8v.2M55.4 147h.4l.1 .2M55.4 146h.4a.2 .2 0 0 1-.2 .2 .2 .2 0 0 1-.2-.2zM55.5 145.9l.3 .3M55.9 146.5v.2M55.9 146.6h-.5l.1 .1M58 158.5v.4M58 159.4l.3 1.1M58.4 156.6l-.3 .8M58.8 152.7a1.61 1.61 0 0 1 1.3-.4v-.2h7.1v.2l2.8 2.8h.3v7.1h-.2l-2.9 2.9v.1h-7.1v-.2a1.65 1.65 0 0 1-1.7-1.1 1.65 1.65 0 0 1 .5-1.9 6.9 6.9 0 0 0-.5-7.7 1.53 1.53 0 0 1 .4-1.6zM59.1 155.3l-.4 .5"/>
<path d="M60.2 154.1l-.8 .7M60.5 154.7h4.6a.8 .8 0 0 1 .8 .8 .8 .8 0 0 1-.8 .8h-4.6M60.6 154.9v1.2M60.7 155v1M60.9 155.1v.8M61 153.6l-.3 .1M62.9 152v-.7h1.5v.7M63.1 152.9l-1.1 .2M63.5 156.4a1.96 1.96 0 0 0 3 .6 1.96 1.96 0 0 0 0-3 1.96 1.96 0 0 0-3 .6 1.95 1.95 0 0 1 3.3-.4 1.95 1.95 0 0 1-.9 3.2M63.5 154.9v1.2M63.6 152.8h.4M63.7 155v1"/>
<path d="M63.9 155.1v.9M65.1 153l.8 .2M65.9 159.9a1.96 1.96 0 0 1 .8 3.1 1.96 1.96 0 0 1-3.2-.4 1.96 1.96 0 0 0 3 .7 1.96 1.96 0 0 0 0-3.1 1.96 1.96 0 0 0-3 .7M66.7 153.6l.5 .3M67.7 154.3l.7 .8M68.7 155.6l.2 .3M69.4 156.9l.2 1M69.5 160l-.2 .7M69.6 158.5v.4M75.2 158.1h7.4v12.6h-7.4zM76 141.5h.8M76.4 141.2v.7"/>
<path d="M82.9 146.4l-.2 .1v.4h.2M82.9 143.6l-.2 .1v.3h.2M83.1 152.7v-.2h-.2l-.1 .2h.5M83.1 146.5h.3l-.3 .4h.3M83.1 143.6h.3v.2h-.2M83.2 143.8l.2 .2h-.3M83.3 151.9v.3l-.4-.2 .1 .2M83.3 152.5l-.2 .1M86.6 142.4h5v4.6h-5zM86.8 142.7h4.5v4.1h-4.5zM88.3 153.6l.2-.1 .1 .3M88.3 153.7l-.1-.2-.1 .3"/>
<path d="M88.4 154.3v-.2h-.2l-.1 .2h.5M88.6 154.1l-.2 .1M94.8 159.4h.7v1.1h-.7zM94.8 156.8h.7v1.2h-.7zM94.8 154.3h.7v1.1h-.7zM94.8 151.8h.7v1.1h-.7zM94.8 149.2h.7v1.1h-.7zM94.8 146.7h.7v1.1h-.7zM94.8 144.2h.7v1.1h-.7zM94.8 141.6h.7v1.1h-.7zM103 141.6h.6v1.1h-.6zM103 144.2h.6v1.1h-.6z"/>
<path d="M103 146.7h.6v1.1h-.6zM103 149.2h.6v1.1h-.6zM103 151.8h.6v1.1h-.6M103 154.3h.6v1.1h-.6M103 156.8h.6v1.2h-.6M103 159.4h.6v1.1h-.6M107.3 153.8l.1 .2 .3-.1v-.1M107.5 153.3h.2M107.6 153.2v.3l-.3-.1M124.4 140l-.1-.2h-.2v.2h.5M125.6 149.6l5.4 .1 .1-.2 1.3 .1 .2 .2v2.6l-.2 .2h-1.3l-.1-.1-5.4 .1-.1-.3zM125.7 155.2h4.2v1.9h-4.2z"/>
<path d="M125.8 149.9v2.3M127 149.9v2.3M127.1 156.1h2.2M127.8 156.1l1-.6v1.3zM127.8 155.5v1.3M131.1 149.9v2.3M132.4 149.9v2.3M137.9 156v2.9l.3 .3h9.6l.3-.3v-2.9M147 148.7l.1 .3 .3-.1 .1-.2M147 147.2l.5 .1-.1 .2h-.4M147 146.7v.3M147 146.8h.5"/>
<path d="M147.1 147.8h.3l.1 .2h-.4zM147.5 146.2v.3M147.5 146.3h-.5l.1 .2M147.6 148.3v.2M150.6 147h.4l.1 .2M151.1 146.6l-.5-.1v.2M56.6 161.3l.1 .6 .8 .1 .3-.2v-.5h-.7v.2M57.8 160.1v.7M57.8 160.5h-1.2l.3 .3M58.7 161.5l.2 .3M59.2 162.2l.7 .8M60.4 163.4l.5 .3"/>
<path d="M60.5 161h4.8a.8 .8 0 0 1 .8 .8 .8 .8 0 0 1-.8 .8h-4.8M60.6 161.2v1.2M60.7 161.3v1M60.9 161.4v.8M61.7 164.1l.8 .3M62.9 165.2v.8h1.5v-.7M63.5 161.2v1.2M63.6 164.5h.4M63.7 161.3v1M63.9 161.4v.8M65.6 164.2l-1 .3M66.9 163.6l-.3 .2"/>
<path d="M68.2 162.5l-.8 .8M68.9 161.5l-.3 .6M88.1 166.5v.3h.2l.2-.3 .1 .1v.2M88.2 168.3l.1 .3h.3l.1-.3M88.4 167.3v-.2h-.2l-.1 .2h.5M88.6 167.1l-.2 .1M88.7 167.8v.3M88.7 168h-.5l.1 .1M93.6 166.6l.2 .2M93.9 167.3v-.2h-.2l-.1 .2h.5M94 166.5l-.2 .3M94 166.5h.1"/>
<path d="M94 166.5l.1 .3h-.3M94.1 167.1l-.2 .1M94.8 169.5h.7v1.2h-.7zM94.8 167h.7v1.1h-.7zM94.8 164.5h.7v1.1h-.7zM94.8 161.9h.7v1.1h-.7zM98.9 171l.2-.3 .3 .1 .1 .2M103 169.5h.6v1.2h-.6M103 161.9h.6v1.1h-.6M103 164.5h.6v1.1h-.6M103 167h.6v1.1h-.6M116.2 163.8l-.2-.1v.2l.2 .2h-.2"/>
<path d="M116.5 163.7l.3 .1-.3 .1M116.6 163.9l.1 .2-.2 .1M128.9 163.8h-.2l.2 .3h-.2M129.2 163.8l.1-.1v.5M129.2 164.2h.3M141.6 163.8h-.2l.2 .3h-.2M141.9 163.8h.2l-.2 .4h.2"/>
<circle cx="58.3" cy="132.6" r="2.86"/>
<circle cx="151.6" cy="132.6" r="2.86"/>
<circle cx="72.6" cy="144.1" r="6.1"/>
<circle cx="72.6" cy="144.1" r="1.27"/>
<circle cx="115.1" cy="150.4" r="3.2"/>
<circle cx="121.8" cy="147.3" r="2.03"/>
<circle cx="58.3" cy="172.3" r="2.86"/>
<circle cx="151.6" cy="172.3" r="2.86"/>
</g>
<path d="M117.6 149.2v2.5M121.1 149.2h1.3" fill="none" stroke="#505050" stroke-width=".32"/>
<g fill="none" stroke="#505050" stroke-width=".21">
<path d="M56.7 137.1h1.3l.6 .6v1.3l-.6 .6 .6 .7v1.2l-.6 .7 .6 .6v1.3l-.6 .6 .6 .7v1.2l-.6 .7h-1.3l-.7-.7v-1.2l.7-.7-.7-.6v-1.3l.7-.6-.7-.7v-1.2l.7-.7-.7-.6v-1.3zM72.3 134.6h.3M72.6 133.8h5v1.5h-5zM77.6 134.6h.3M85.8 136.9h-3a2.69 2.69 0 0 1 0-4.6h3a2.7 2.7 0 0 1 0 4.6M95.4 132.7l.6-.7h1.3l.6 .7 .7-.7h1.2l.7 .7 .6-.7h1.3l.6 .7 .7-.7h1.2l.7 .7 .6-.7h1.3l.6 .7v1.2l-.6 .7h-1.3l-.6-.7-.7 .7h-1.2l-.7-.7-.6 .7h-1.3l-.6-.7-.7 .7h-1.2l-.7-.7-.6 .7h-1.3l-.6-.7zM111.8 139v-8.1h9v13.5h-2.1M111.8 133.8h9M122.3 137.1h1.5v5.1h-1.5zM123 136.8v.3M125.2 132.5h10.2v10h-10.2zM125.2 132l1.7-.5h6.8l1.7 .5v.4h-10.2z"/>
<path d="M125.2 132.2h10.2M125.2 132h10.2M125.7 131.8h9.2M126.4 131.7h7.9M143.6 139.6h1.3M144.3 133.9v1.3M144.3 139v1.3M151.9 137.1h1.3l.6 .6v1.3l-.6 .6 .6 .7v1.2l-.6 .7 .6 .6v1.3l-.6 .6 .6 .7v1.2l-.6 .7h-1.3l-.6-.7v-1.2l.6-.7-.6-.6v-1.3l.6-.6-.6-.7v-1.2l.6-.7-.6-.6v-1.3zM81 149.8h1.5v5.1h-1.5zM81.8 149.5v.3M81.8 154.9v.2M82.1 142.5h.4"/>
<path d="M82.1 145.4h.4M82.5 141.9v1.2M82.5 144.7v1.3M83.5 142.5h.5M83.5 141.9v1.2M83.5 144.7v1.3M83.5 145.4h.5M88.9 151.4h1.5v5.1h-1.5zM89.7 151.1v.3M89.7 156.5v.2M105.6 153.1h1.2M105.6 154.1h1.2"/>
<path d="M106.2 152.6v.5M106.2 154.1v.5M111.8 143.7v.7h2.2M123 142.2v.2M143.6 150.1h1.3M144.3 144.4v1.3M144.3 149.5v1.2M86.5 167.7h1.3M86.5 168.7h1.3M87.1 167.2v.5M87.1 168.7v.5M88.9 164.4h1.5v5.1h-1.5z"/>
<path d="M89.7 164.1v.3M89.7 169.5v.2M91.8 164.4h1.5v5.1h-1.5zM92.5 164.1v.3M92.5 169.5v.2M113.3 165l.5-.5h5.1l.5 .5v5.1l-.5 .5h-5.1l-.5-.5zM113.8 166.3v.7l.4 .9M113.8 168.1v.7M126.5 164.5h5.1l.5 .5v5.1l-.5 .5h-5.1l-.5-.5v-5.1zM126.5 166.3v.7l.4 .9M126.5 168.1v.7M139.2 164.5h5.1l.5 .5v5.1l-.5 .5h-5.1l-.5-.5v-5.1z"/>
<path d="M139.2 166.3v.7l.4 .9M139.2 168.1v.7"/>
<circle cx="141.7" cy="137.1" r="5"/>
<circle cx="141.7" cy="147.6" r="5"/>
<circle cx="116.4" cy="167.6" r="1.78"/>
<circle cx="129.1" cy="167.6" r="1.78"/>
<circle cx="141.7" cy="167.6" r="1.78"/>
</g>
<g fill="#505050" stroke="#505050" stroke-width=".18">
<path d="M126.1 155.2h.5v1.9h-.5z"/>
<path d="M129.9 155.7h.6v.9h-.6z"/>
<path d="M125.1 155.7h.6v.9h-.6z"/>
<path d="M123.5 150.8h2v.6h-2z"/>
<path d="M132.6 150.8h1.9v.6h-1.9z"/>
<path d="M126.4 142.4h1v1.7h-1z"/>
<path d="M128.1 142.4h1v1.7h-1z"/>
<path d="M129.8 142.4h1v1.7h-1z"/>
<path d="M131.5 142.4h1v1.7h-1z"/>
<path d="M133.2 142.4h1v1.7h-1z"/>
<path d="M137.7 154.9h1.9v1.2h-1.9z"/>
<path d="M139.6 154.9h1.8v.7h-1.8z"/>
<path d="M141.4 154.9h.7v1.2h-.7z"/>
<path d="M142.1 154.9h1.8v.7h-1.8z"/>
<path d="M143.9 154.9h.8v1.2h-.8z"/>
<path d="M144.7 154.9h1.7v.7h-1.7z"/>
<path d="M146.4 154.9h1.9v1.2h-1.9z"/>
<path d="M67.1 158.5h2.2v.4h-2.2z"/>
<path d="M67.9 157.6h.4v2.2h-.4z"/>
<path d="M126.4 144.1h1v2.1h-1z"/>
<path d="M128.1 144.1h1v2.1h-1z"/>
<path d="M129.8 144.1h1v2.1h-1z"/>
<path d="M131.5 144.1h1v2.1h-1z"/>
<path d="M133.2 144.1h1v2.1h-1z"/>
<path d="M152.3 138.1h.5v.5h-.5z"/>
<path d="M152.3 140.7h.5v.5h-.5z"/>
<path d="M152.3 143.2h.5v.5h-.5z"/>
<path d="M152.3 145.7h.5v.5h-.5z"/>
<path d="M57.1 138.1h.5v.5h-.5z"/>
<path d="M57.1 140.7h.5v.5h-.5z"/>
<path d="M57.1 143.2h.5v.5h-.5z"/>
<path d="M57.1 145.7h.5v.5h-.5z"/>
<path d="M139.6 155.6h1.8v.5h-1.8z"/>
<path d="M142.1 155.6h1.8v.5h-1.8z"/>
<path d="M144.7 155.6h1.7v.5h-1.7z"/>
<path d="M73.8 158.5h1.3v.4h-1.3z"/>
<path d="M73.8 159.7h1.3v.5h-1.3z"/>
<path d="M73.8 161h1.3v.4h-1.3z"/>
<path d="M73.8 162.3h1.3v.4h-1.3z"/>
<path d="M73.8 163.5h1.3v.5h-1.3z"/>
<path d="M73.8 164.8h1.3v.4h-1.3z"/>
<path d="M73.8 166.1h1.3v.4h-1.3z"/>
<path d="M73.8 167.3h1.3v.5h-1.3z"/>
<path d="M73.8 168.6h1.3v.4h-1.3z"/>
<path d="M73.8 169.9h1.3v.4h-1.3z"/>
<path d="M82.7 158.5h1.3v.4h-1.3z"/>
<path d="M82.7 159.7h1.3v.5h-1.3z"/>
<path d="M82.7 161h1.3v.4h-1.3z"/>
<path d="M82.7 162.3h1.3v.4h-1.3z"/>
<path d="M82.7 163.5h1.3v.5h-1.3z"/>
<path d="M82.7 164.8h1.3v.4h-1.3z"/>
<path d="M82.7 166.1h1.3v.4h-1.3z"/>
<path d="M82.7 167.3h1.3v.5h-1.3z"/>
<path d="M82.7 168.6h1.3v.4h-1.3z"/>
<path d="M82.7 169.9h1.3v.4h-1.3z"/>
<path d="M87 147h.2v.8h-.2z"/>
<path d="M87.7 147h.2v.8h-.2z"/>
<path d="M88.3 147h.2v.8h-.2z"/>
<path d="M88.9 147h.3v.8h-.3z"/>
<path d="M89.6 147h.2v.8h-.2z"/>
<path d="M90.3 147h.2v.8h-.2z"/>
<path d="M90.9 147h.2v.8h-.2z"/>
<path d="M90.9 141.6h.2v.9h-.2z"/>
<path d="M90.3 141.6h.2v.9h-.2z"/>
<path d="M89.6 141.6h.2v.9h-.2z"/>
<path d="M88.9 141.6h.3v.9h-.3z"/>
<path d="M88.3 141.6h.2v.9h-.2z"/>
<path d="M87.7 141.6h.2v.9h-.2z"/>
<path d="M87 141.6h.2v.9h-.2z"/>
<path d="M96.4 133h.5v.5h-.5z"/>
<path d="M99 133h.5v.5h-.5z"/>
<path d="M101.5 133h.5v.5h-.5z"/>
<path d="M104 133h.5v.5h-.5z"/>
<path d="M106.6 133h.5v.5h-.5z"/>
</g>
<g fill="#505050" stroke="#505050" stroke-width=".18">
<path d="M75.7 141a.84 .84 0 0 1 1.4 .1 .84 .84 0 0 1-.5 1.2 .84 .84 0 0 1-1.1-.8h.2a.69 .69 0 0 1 .9-.6 .69 .69 0 0 1 .2 1.1 .69 .69 0 0 1-1.1-.2v-.3h-.2z" fill-rule="evenodd"/>
<path d="M81.2 169.3a.61 .61 0 0 1 1 .1 .61 .61 0 0 1-.3 .9 .61 .61 0 0 1-.8-.5h.1a.46 .46 0 0 1 .7-.4 .46 .46 0 0 1 .1 .8 .46 .46 0 0 1-.8-.3v-.1h-.1z" fill-rule="evenodd"/>
<path d="M87.1 145.5a.53 .53 0 0 1 .8 .2 .53 .53 0 0 1-.4 .8 .53 .53 0 0 1-.6-.6h.2a.38 .38 0 0 1 .5-.3 .38 .38 0 0 1 .1 .6 .38 .38 0 0 1-.6-.1v-.2h-.2z" fill-rule="evenodd"/>
<circle cx="138.4" cy="158.6" r=".25"/>
</g>
<path d="M124 156.1h1.3M130.3 156.1h1.3" fill="none" stroke="#505050" stroke-width=".87"/>
<path d="M122.7 151.1h1.1M134.3 151.1h1.1" fill="none" stroke="#505050" stroke-width=".61"/>
<g fill="none" stroke="#000" stroke-width=".18">
<path d="M74.1 134.6h2M75.1 133.5v2.1M83.3 134.6h2M84.3 133.5v2.1M94.4 137.1h2M95.4 136.1v2M105.8 133.3h2M106.8 132.3v2M115.3 130.8h2.1M116.4 129.8v2M122 139.6h2M123 138.6v2.1"/>
<path d="M129.3 139.6h2M130.3 138.6v2.1M140.7 137.1h2M141.7 136.1v2M56.3 146h2M57.3 145v2M62.7 158.7h2M63.7 157.7v2M71.5 144.1h2.1M72.6 143.1v2M80.8 152.3h2M81.8 151.3v2.1"/>
<path d="M82 145.4h2M82 142.5h2M83 141.5v2M83 144.3v2.1M88.2 144.7h1.7M88.7 153.9h2M89 143.8v1.8M89.7 152.9v2M105.2 153.6h2M106.2 152.6v2M114.1 150.4h2M115.1 149.4v2"/>
<path d="M120.7 147.3h2.1M121.8 146.2v2.1M126.8 156.1h2M127.8 155.1v2.1M128 151.1h2.1M129.1 150.1v2M140.7 147.6h2M141.7 146.6v2M142 154.9h2M143 153.9v2M151.5 146h2M152.5 145v2"/>
<path d="M77.9 164.4h2M78.9 163.4v2M86.1 168.2h2.1M87.1 167.2v2M88.7 166.9h2M89.7 165.9v2M91.5 166.9h2.1M92.5 165.9v2M115.3 167.6h2.1M116.4 166.5v2.1M128 167.6h2.1M129.1 166.5v2.1"/>
<path d="M140.7 167.6h2M141.7 166.5v2.1"/>
</g>
<g fill="none" stroke="#f90" stroke-width=".18">
<path d="M56.2 130.3a2.4 2.4 0 0 1 1.5-.5h94.4a2.26 2.26 0 0 1 2.3 2.2v40.9a2.29 2.29 0 0 1-2.3 2.3h-94.4a2.29 2.29 0 0 1-2.3-2.3v-40.8a2.31 2.31 0 0 1 .8-1.8z"/>
<circle cx="58.3" cy="172.3" r="1.5"/>
</g>
<circle cx="58.3" cy="172.3" r="1.5" fill="#fff" stroke="#000" stroke-width=".18"/>
<circle cx="58.3" cy="132.6" r="1.5" fill="none" stroke="#f90" stroke-width=".18"/>
<circle cx="58.3" cy="132.6" r="1.5" fill="#fff" stroke="#000" stroke-width=".18"/>
<circle cx="151.6" cy="132.6" r="1.5" fill="none" stroke="#f90" stroke-width=".18"/>
<circle cx="151.6" cy="132.6" r="1.5" fill="#fff" stroke="#000" stroke-width=".18"/>
<circle cx="151.6" cy="172.3" r="1.5" fill="none" stroke="#f90" stroke-width=".18"/>
<circle cx="151.6" cy="172.3" r="1.5" fill="#fff" stroke="#000" stroke-width=".18"/>
<g fill="none" stroke="#505050" stroke-width=".18">
<path d="M59.3 131.6l-2 2M152.6 131.6l-2 2M59.3 171.3l-2 2M152.6 171.3l-2 2"/>
<circle cx="58.3" cy="132.6" r=".99"/>
<circle cx="151.6" cy="132.6" r=".99"/>
<circle cx="58.3" cy="172.3" r=".99"/>
<circle cx="151.6" cy="172.3" r=".99"/>
</g>
<use href="#words"/>
</svg>
